VERSION 5.7 ;
  NOWIREEXTENSIONATPIN ON ;
  DIVIDERCHAR "/" ;
  BUSBITCHARS "[]" ;
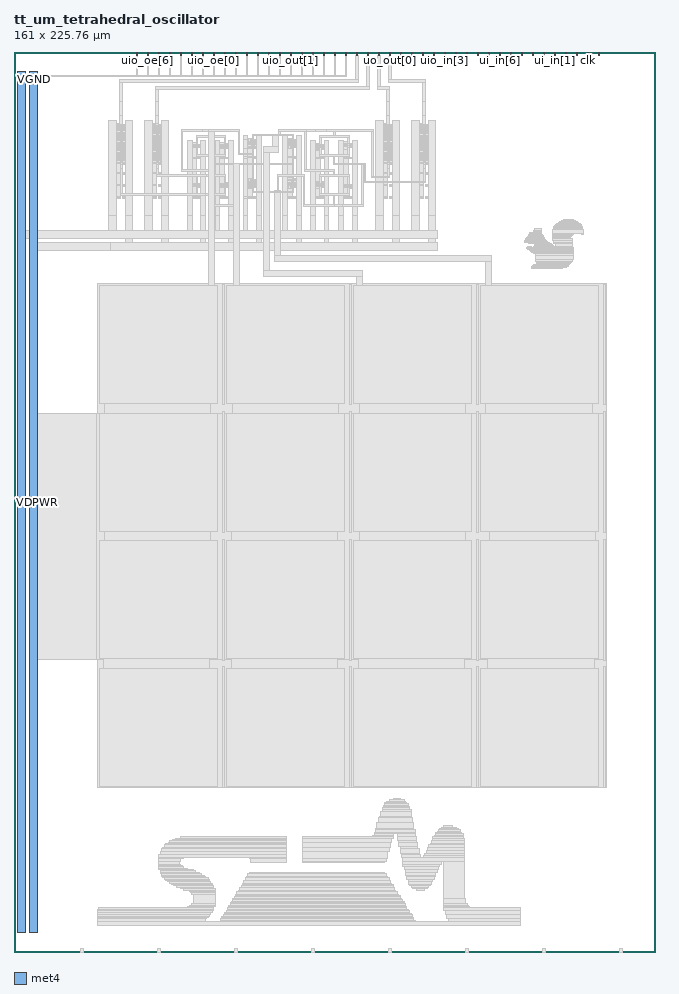
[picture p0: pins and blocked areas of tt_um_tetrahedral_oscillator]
MACRO tt_um_tetrahedral_oscillator
  CLASS BLOCK ;
  FOREIGN tt_um_tetrahedral_oscillator ;
  ORIGIN 0.000 0.000 ;
  SIZE 161.000 BY 225.760 ;
  PIN clk
    DIRECTION INPUT ;
    USE SIGNAL ;
    PORT
      LAYER met4 ;
        RECT 143.830 224.760 144.130 225.760 ;
    END
  END clk
  PIN ena
    DIRECTION INPUT ;
    USE SIGNAL ;
    PORT
      LAYER met4 ;
        RECT 146.590 224.760 146.890 225.760 ;
    END
  END ena
  PIN rst_n
    DIRECTION INPUT ;
    USE SIGNAL ;
    PORT
      LAYER met4 ;
        RECT 141.070 224.760 141.370 225.760 ;
    END
  END rst_n
  PIN ui_in[0]
    DIRECTION INPUT ;
    USE SIGNAL ;
    PORT
      LAYER met4 ;
        RECT 138.310 224.760 138.610 225.760 ;
    END
  END ui_in[0]
  PIN ui_in[1]
    DIRECTION INPUT ;
    USE SIGNAL ;
    PORT
      LAYER met4 ;
        RECT 135.550 224.760 135.850 225.760 ;
    END
  END ui_in[1]
  PIN ui_in[2]
    DIRECTION INPUT ;
    USE SIGNAL ;
    PORT
      LAYER met4 ;
        RECT 132.790 224.760 133.090 225.760 ;
    END
  END ui_in[2]
  PIN ui_in[3]
    DIRECTION INPUT ;
    USE SIGNAL ;
    PORT
      LAYER met4 ;
        RECT 130.030 224.760 130.330 225.760 ;
    END
  END ui_in[3]
  PIN ui_in[4]
    DIRECTION INPUT ;
    USE SIGNAL ;
    PORT
      LAYER met4 ;
        RECT 127.270 224.760 127.570 225.760 ;
    END
  END ui_in[4]
  PIN ui_in[5]
    DIRECTION INPUT ;
    USE SIGNAL ;
    PORT
      LAYER met4 ;
        RECT 124.510 224.760 124.810 225.760 ;
    END
  END ui_in[5]
  PIN ui_in[6]
    DIRECTION INPUT ;
    USE SIGNAL ;
    PORT
      LAYER met4 ;
        RECT 121.750 224.760 122.050 225.760 ;
    END
  END ui_in[6]
  PIN ui_in[7]
    DIRECTION INPUT ;
    USE SIGNAL ;
    PORT
      LAYER met4 ;
        RECT 118.990 224.760 119.290 225.760 ;
    END
  END ui_in[7]
  PIN uio_in[0]
    DIRECTION INPUT ;
    USE SIGNAL ;
    PORT
      LAYER met4 ;
        RECT 116.230 224.760 116.530 225.760 ;
    END
  END uio_in[0]
  PIN uio_in[1]
    DIRECTION INPUT ;
    USE SIGNAL ;
    PORT
      LAYER met4 ;
        RECT 113.470 224.760 113.770 225.760 ;
    END
  END uio_in[1]
  PIN uio_in[2]
    DIRECTION INPUT ;
    USE SIGNAL ;
    PORT
      LAYER met4 ;
        RECT 110.710 224.760 111.010 225.760 ;
    END
  END uio_in[2]
  PIN uio_in[3]
    DIRECTION INPUT ;
    USE SIGNAL ;
    PORT
      LAYER met4 ;
        RECT 107.950 224.760 108.250 225.760 ;
    END
  END uio_in[3]
  PIN uio_in[4]
    DIRECTION INPUT ;
    USE SIGNAL ;
    PORT
      LAYER met4 ;
        RECT 105.190 224.760 105.490 225.760 ;
    END
  END uio_in[4]
  PIN uio_in[5]
    DIRECTION INPUT ;
    USE SIGNAL ;
    PORT
      LAYER met4 ;
        RECT 102.430 224.760 102.730 225.760 ;
    END
  END uio_in[5]
  PIN uio_in[6]
    DIRECTION INPUT ;
    USE SIGNAL ;
    PORT
      LAYER met4 ;
        RECT 99.670 224.760 99.970 225.760 ;
    END
  END uio_in[6]
  PIN uio_in[7]
    DIRECTION INPUT ;
    USE SIGNAL ;
    PORT
      LAYER met4 ;
        RECT 96.910 224.760 97.210 225.760 ;
    END
  END uio_in[7]
  PIN uio_oe[0]
    DIRECTION OUTPUT ;
    USE SIGNAL ;
    ANTENNADIFFAREA 14.596000 ;
    PORT
      LAYER met4 ;
        RECT 49.990 224.760 50.290 225.760 ;
    END
  END uio_oe[0]
  PIN uio_oe[1]
    DIRECTION OUTPUT ;
    USE SIGNAL ;
    ANTENNADIFFAREA 14.596000 ;
    PORT
      LAYER met4 ;
        RECT 47.230 224.760 47.530 225.760 ;
    END
  END uio_oe[1]
  PIN uio_oe[2]
    DIRECTION OUTPUT ;
    USE SIGNAL ;
    ANTENNADIFFAREA 14.596000 ;
    PORT
      LAYER met4 ;
        RECT 44.470 224.760 44.770 225.760 ;
    END
  END uio_oe[2]
  PIN uio_oe[3]
    DIRECTION OUTPUT ;
    USE SIGNAL ;
    ANTENNADIFFAREA 14.596000 ;
    PORT
      LAYER met4 ;
        RECT 41.710 224.760 42.010 225.760 ;
    END
  END uio_oe[3]
  PIN uio_oe[4]
    DIRECTION OUTPUT ;
    USE SIGNAL ;
    ANTENNADIFFAREA 14.596000 ;
    PORT
      LAYER met4 ;
        RECT 38.950 224.760 39.250 225.760 ;
    END
  END uio_oe[4]
  PIN uio_oe[5]
    DIRECTION OUTPUT ;
    USE SIGNAL ;
    ANTENNADIFFAREA 14.596000 ;
    PORT
      LAYER met4 ;
        RECT 36.190 224.760 36.490 225.760 ;
    END
  END uio_oe[5]
  PIN uio_oe[6]
    DIRECTION OUTPUT ;
    USE SIGNAL ;
    ANTENNADIFFAREA 14.596000 ;
    PORT
      LAYER met4 ;
        RECT 33.430 224.760 33.730 225.760 ;
    END
  END uio_oe[6]
  PIN uio_oe[7]
    DIRECTION OUTPUT ;
    USE SIGNAL ;
    ANTENNADIFFAREA 14.596000 ;
    PORT
      LAYER met4 ;
        RECT 30.670 224.760 30.970 225.760 ;
    END
  END uio_oe[7]
  PIN uio_out[0]
    DIRECTION OUTPUT ;
    USE SIGNAL ;
    ANTENNADIFFAREA 14.596000 ;
    PORT
      LAYER met4 ;
        RECT 72.070 224.760 72.370 225.760 ;
    END
  END uio_out[0]
  PIN uio_out[1]
    DIRECTION OUTPUT ;
    USE SIGNAL ;
    ANTENNADIFFAREA 14.596000 ;
    PORT
      LAYER met4 ;
        RECT 69.310 224.760 69.610 225.760 ;
    END
  END uio_out[1]
  PIN uio_out[2]
    DIRECTION OUTPUT ;
    USE SIGNAL ;
    ANTENNADIFFAREA 14.596000 ;
    PORT
      LAYER met4 ;
        RECT 66.550 224.760 66.850 225.760 ;
    END
  END uio_out[2]
  PIN uio_out[3]
    DIRECTION OUTPUT ;
    USE SIGNAL ;
    ANTENNADIFFAREA 14.596000 ;
    PORT
      LAYER met4 ;
        RECT 63.790 224.760 64.090 225.760 ;
    END
  END uio_out[3]
  PIN uio_out[4]
    DIRECTION OUTPUT ;
    USE SIGNAL ;
    ANTENNADIFFAREA 14.596000 ;
    PORT
      LAYER met4 ;
        RECT 61.030 224.760 61.330 225.760 ;
    END
  END uio_out[4]
  PIN uio_out[5]
    DIRECTION OUTPUT ;
    USE SIGNAL ;
    ANTENNADIFFAREA 14.596000 ;
    PORT
      LAYER met4 ;
        RECT 58.270 224.760 58.570 225.760 ;
    END
  END uio_out[5]
  PIN uio_out[6]
    DIRECTION OUTPUT ;
    USE SIGNAL ;
    ANTENNADIFFAREA 14.596000 ;
    PORT
      LAYER met4 ;
        RECT 55.510 224.760 55.810 225.760 ;
    END
  END uio_out[6]
  PIN uio_out[7]
    DIRECTION OUTPUT ;
    USE SIGNAL ;
    ANTENNADIFFAREA 14.596000 ;
    PORT
      LAYER met4 ;
        RECT 52.750 224.760 53.050 225.760 ;
    END
  END uio_out[7]
  PIN uo_out[0]
    DIRECTION OUTPUT ;
    USE SIGNAL ;
    ANTENNADIFFAREA 3.564000 ;
    PORT
      LAYER met4 ;
        RECT 94.150 224.760 94.450 225.760 ;
    END
  END uo_out[0]
  PIN uo_out[1]
    DIRECTION OUTPUT ;
    USE SIGNAL ;
    ANTENNADIFFAREA 3.564000 ;
    PORT
      LAYER met4 ;
        RECT 91.390 224.760 91.690 225.760 ;
    END
  END uo_out[1]
  PIN uo_out[2]
    DIRECTION OUTPUT ;
    USE SIGNAL ;
    ANTENNADIFFAREA 3.564000 ;
    PORT
      LAYER met4 ;
        RECT 88.630 224.760 88.930 225.760 ;
    END
  END uo_out[2]
  PIN uo_out[3]
    DIRECTION OUTPUT ;
    USE SIGNAL ;
    ANTENNADIFFAREA 3.564000 ;
    PORT
      LAYER met4 ;
        RECT 85.870 224.760 86.170 225.760 ;
    END
  END uo_out[3]
  PIN uo_out[4]
    DIRECTION OUTPUT ;
    USE SIGNAL ;
    ANTENNADIFFAREA 14.596000 ;
    PORT
      LAYER met4 ;
        RECT 83.110 224.760 83.410 225.760 ;
    END
  END uo_out[4]
  PIN uo_out[5]
    DIRECTION OUTPUT ;
    USE SIGNAL ;
    ANTENNADIFFAREA 14.596000 ;
    PORT
      LAYER met4 ;
        RECT 80.350 224.760 80.650 225.760 ;
    END
  END uo_out[5]
  PIN uo_out[6]
    DIRECTION OUTPUT ;
    USE SIGNAL ;
    ANTENNADIFFAREA 14.596000 ;
    PORT
      LAYER met4 ;
        RECT 77.590 224.760 77.890 225.760 ;
    END
  END uo_out[6]
  PIN uo_out[7]
    DIRECTION OUTPUT ;
    USE SIGNAL ;
    ANTENNADIFFAREA 14.596000 ;
    PORT
      LAYER met4 ;
        RECT 74.830 224.760 75.130 225.760 ;
    END
  END uo_out[7]
  PIN VDPWR
    DIRECTION INOUT ;
    USE POWER ;
    PORT
      LAYER met4 ;
        RECT 1.000 5.000 3.000 220.760 ;
    END
  END VDPWR
  PIN VGND
    DIRECTION INOUT ;
    USE GROUND ;
    PORT
      LAYER met4 ;
        RECT 4.000 5.000 6.000 220.760 ;
    END
  END VGND
  OBS
      LAYER nwell ;
        RECT 25.205 188.930 26.810 207.915 ;
      LAYER pwell ;
        RECT 27.100 197.925 28.010 207.360 ;
        RECT 27.100 197.755 28.200 197.925 ;
        RECT 27.100 197.610 28.010 197.755 ;
        RECT 27.140 195.135 27.925 195.565 ;
        RECT 27.140 192.135 27.925 192.565 ;
        RECT 27.140 189.135 27.925 189.565 ;
      LAYER nwell ;
        RECT 34.205 188.930 35.810 207.940 ;
      LAYER pwell ;
        RECT 36.100 197.950 37.010 207.385 ;
        RECT 36.100 197.780 37.200 197.950 ;
        RECT 36.100 197.635 37.010 197.780 ;
        RECT 36.140 195.135 36.925 195.565 ;
        RECT 36.140 192.135 36.925 192.565 ;
        RECT 36.140 189.135 36.925 189.565 ;
      LAYER nwell ;
        RECT 44.205 188.930 45.810 203.015 ;
      LAYER pwell ;
        RECT 47.030 202.615 47.200 202.680 ;
        RECT 46.100 202.510 47.200 202.615 ;
        RECT 46.100 201.685 47.010 202.510 ;
        RECT 46.140 198.935 46.925 199.365 ;
        RECT 46.100 191.945 47.010 192.770 ;
        RECT 46.100 191.840 47.200 191.945 ;
        RECT 47.030 191.775 47.200 191.840 ;
        RECT 46.140 189.135 46.925 189.565 ;
      LAYER nwell ;
        RECT 51.205 188.930 52.810 202.985 ;
      LAYER pwell ;
        RECT 53.100 202.650 54.010 202.780 ;
        RECT 53.100 202.480 54.200 202.650 ;
        RECT 53.100 201.430 54.010 202.480 ;
      LAYER nwell ;
        RECT 58.205 201.430 59.815 204.110 ;
      LAYER pwell ;
        RECT 60.105 201.930 61.015 203.860 ;
      LAYER nwell ;
        RECT 68.230 203.035 69.840 204.110 ;
      LAYER pwell ;
        RECT 60.105 201.760 61.195 201.930 ;
        RECT 60.105 201.670 61.015 201.760 ;
      LAYER nwell ;
        RECT 68.205 201.430 69.840 203.035 ;
      LAYER pwell ;
        RECT 70.130 203.780 71.040 203.870 ;
        RECT 70.130 203.610 71.220 203.780 ;
        RECT 70.130 201.680 71.040 203.610 ;
      LAYER nwell ;
        RECT 82.210 202.835 83.815 203.185 ;
        RECT 75.205 202.785 76.810 202.835 ;
      LAYER pwell ;
        RECT 53.140 198.935 53.925 199.365 ;
      LAYER nwell ;
        RECT 58.205 194.090 59.810 201.430 ;
      LAYER pwell ;
        RECT 60.140 199.135 60.925 199.565 ;
      LAYER nwell ;
        RECT 68.205 194.160 69.810 201.430 ;
        RECT 75.205 201.025 76.815 202.785 ;
      LAYER pwell ;
        RECT 77.105 202.450 78.015 202.580 ;
        RECT 77.105 202.280 78.205 202.450 ;
        RECT 77.105 201.230 78.015 202.280 ;
      LAYER nwell ;
        RECT 82.205 201.425 83.815 202.835 ;
      LAYER pwell ;
        RECT 85.035 202.785 85.205 202.850 ;
        RECT 84.105 202.680 85.205 202.785 ;
        RECT 84.105 201.855 85.015 202.680 ;
        RECT 70.140 199.135 70.925 199.565 ;
        RECT 53.100 191.960 54.010 193.010 ;
        RECT 53.100 191.790 54.200 191.960 ;
        RECT 53.100 191.660 54.010 191.790 ;
      LAYER nwell ;
        RECT 58.200 191.410 59.810 194.090 ;
      LAYER pwell ;
        RECT 60.100 191.910 61.010 193.840 ;
        RECT 60.100 191.740 61.190 191.910 ;
        RECT 60.100 191.650 61.010 191.740 ;
      LAYER nwell ;
        RECT 68.200 191.480 69.810 194.160 ;
      LAYER pwell ;
        RECT 70.100 193.830 71.010 193.920 ;
        RECT 70.100 193.660 71.190 193.830 ;
        RECT 70.100 191.730 71.010 193.660 ;
      LAYER nwell ;
        RECT 75.205 193.400 76.810 201.025 ;
      LAYER pwell ;
        RECT 77.140 198.935 77.925 199.365 ;
      LAYER nwell ;
        RECT 75.200 191.640 76.810 193.400 ;
      LAYER pwell ;
        RECT 77.095 192.145 78.005 193.195 ;
        RECT 77.095 191.975 78.195 192.145 ;
        RECT 77.095 191.845 78.005 191.975 ;
        RECT 53.140 189.135 53.925 189.565 ;
      LAYER nwell ;
        RECT 58.205 188.930 59.810 191.410 ;
      LAYER pwell ;
        RECT 60.140 189.135 60.925 189.565 ;
      LAYER nwell ;
        RECT 68.205 188.930 69.810 191.480 ;
      LAYER pwell ;
        RECT 70.140 189.135 70.925 189.565 ;
      LAYER nwell ;
        RECT 75.205 188.930 76.810 191.640 ;
      LAYER pwell ;
        RECT 77.140 189.135 77.925 189.565 ;
      LAYER nwell ;
        RECT 82.205 188.930 83.810 201.425 ;
      LAYER pwell ;
        RECT 84.140 198.935 84.925 199.365 ;
        RECT 84.100 191.740 85.010 192.565 ;
        RECT 84.100 191.635 85.200 191.740 ;
        RECT 85.030 191.570 85.200 191.635 ;
        RECT 84.140 189.135 84.925 189.565 ;
      LAYER nwell ;
        RECT 92.205 188.920 93.810 207.935 ;
      LAYER pwell ;
        RECT 94.100 197.945 95.010 207.380 ;
        RECT 94.100 197.775 95.200 197.945 ;
        RECT 94.100 197.630 95.010 197.775 ;
        RECT 94.140 195.135 94.925 195.565 ;
        RECT 94.140 192.135 94.925 192.565 ;
        RECT 94.140 189.135 94.925 189.565 ;
      LAYER nwell ;
        RECT 101.205 188.930 102.810 207.940 ;
      LAYER pwell ;
        RECT 103.100 197.950 104.010 207.385 ;
        RECT 103.100 197.780 104.200 197.950 ;
        RECT 103.100 197.635 104.010 197.780 ;
        RECT 103.140 195.135 103.925 195.565 ;
        RECT 103.140 192.135 103.925 192.565 ;
        RECT 103.140 189.135 103.925 189.565 ;
      LAYER li1 ;
        RECT 25.310 207.190 25.480 207.725 ;
        RECT 25.755 207.365 27.750 207.640 ;
        RECT 26.500 207.260 27.380 207.365 ;
        RECT 25.310 207.020 26.280 207.190 ;
        RECT 25.310 206.350 25.480 207.020 ;
        RECT 26.500 206.850 26.670 207.260 ;
        RECT 25.650 206.520 26.670 206.850 ;
        RECT 25.310 206.180 26.280 206.350 ;
        RECT 25.310 205.510 25.480 206.180 ;
        RECT 26.500 206.010 26.670 206.520 ;
        RECT 25.650 205.680 26.670 206.010 ;
        RECT 25.310 205.340 26.280 205.510 ;
        RECT 25.310 204.670 25.480 205.340 ;
        RECT 26.500 205.170 26.670 205.680 ;
        RECT 25.650 204.840 26.670 205.170 ;
        RECT 25.310 204.500 26.280 204.670 ;
        RECT 25.310 203.830 25.480 204.500 ;
        RECT 26.500 204.330 26.670 204.840 ;
        RECT 25.650 204.000 26.670 204.330 ;
        RECT 25.310 203.660 26.280 203.830 ;
        RECT 25.310 202.990 25.480 203.660 ;
        RECT 26.500 203.490 26.670 204.000 ;
        RECT 25.650 203.160 26.670 203.490 ;
        RECT 25.310 202.820 26.280 202.990 ;
        RECT 25.310 202.150 25.480 202.820 ;
        RECT 26.500 202.650 26.670 203.160 ;
        RECT 25.650 202.320 26.670 202.650 ;
        RECT 25.310 201.980 26.280 202.150 ;
        RECT 25.310 201.310 25.480 201.980 ;
        RECT 26.500 201.810 26.670 202.320 ;
        RECT 25.650 201.480 26.670 201.810 ;
        RECT 25.310 201.140 26.280 201.310 ;
        RECT 25.310 200.470 25.480 201.140 ;
        RECT 26.500 200.970 26.670 201.480 ;
        RECT 25.650 200.640 26.670 200.970 ;
        RECT 26.840 200.470 27.040 207.015 ;
        RECT 27.210 206.850 27.380 207.260 ;
        RECT 28.030 207.190 28.200 207.725 ;
        RECT 27.550 207.020 28.200 207.190 ;
        RECT 27.210 206.520 27.855 206.850 ;
        RECT 27.210 206.010 27.380 206.520 ;
        RECT 28.030 206.350 28.200 207.020 ;
        RECT 27.550 206.180 28.200 206.350 ;
        RECT 27.210 205.680 27.855 206.010 ;
        RECT 27.210 205.170 27.380 205.680 ;
        RECT 28.030 205.510 28.200 206.180 ;
        RECT 27.550 205.340 28.200 205.510 ;
        RECT 27.210 204.840 27.855 205.170 ;
        RECT 27.210 204.330 27.380 204.840 ;
        RECT 28.030 204.670 28.200 205.340 ;
        RECT 27.550 204.500 28.200 204.670 ;
        RECT 27.210 204.000 27.855 204.330 ;
        RECT 27.210 203.490 27.380 204.000 ;
        RECT 28.030 203.830 28.200 204.500 ;
        RECT 27.550 203.660 28.200 203.830 ;
        RECT 27.210 203.160 27.855 203.490 ;
        RECT 27.210 202.650 27.380 203.160 ;
        RECT 28.030 202.990 28.200 203.660 ;
        RECT 27.550 202.820 28.200 202.990 ;
        RECT 27.210 202.570 27.855 202.650 ;
        RECT 27.210 202.400 27.860 202.570 ;
        RECT 27.210 202.320 27.855 202.400 ;
        RECT 27.210 201.810 27.380 202.320 ;
        RECT 28.030 202.150 28.200 202.820 ;
        RECT 27.550 201.980 28.200 202.150 ;
        RECT 27.210 201.730 27.855 201.810 ;
        RECT 27.210 201.560 27.860 201.730 ;
        RECT 27.210 201.480 27.855 201.560 ;
        RECT 27.210 200.970 27.380 201.480 ;
        RECT 28.030 201.310 28.200 201.980 ;
        RECT 27.550 201.140 28.200 201.310 ;
        RECT 27.210 200.890 27.855 200.970 ;
        RECT 27.210 200.640 27.860 200.890 ;
        RECT 28.030 200.470 28.200 201.140 ;
        RECT 25.310 200.300 26.280 200.470 ;
        RECT 25.310 199.630 25.480 200.300 ;
        RECT 26.500 200.295 27.380 200.470 ;
        RECT 27.550 200.300 28.200 200.470 ;
        RECT 26.500 200.130 26.670 200.295 ;
        RECT 25.650 199.800 26.670 200.130 ;
        RECT 27.210 200.130 27.380 200.295 ;
        RECT 25.310 199.460 26.280 199.630 ;
        RECT 25.310 198.790 25.480 199.460 ;
        RECT 26.500 199.290 26.670 199.800 ;
        RECT 25.650 198.960 26.670 199.290 ;
        RECT 25.310 198.620 26.280 198.790 ;
        RECT 25.310 197.950 25.480 198.620 ;
        RECT 26.500 198.450 26.670 198.960 ;
        RECT 25.650 198.120 26.670 198.450 ;
        RECT 25.310 197.780 26.670 197.950 ;
        RECT 25.310 197.605 25.480 197.780 ;
        RECT 26.840 197.690 27.040 200.090 ;
        RECT 27.210 199.800 27.855 200.130 ;
        RECT 27.210 199.290 27.380 199.800 ;
        RECT 28.030 199.630 28.200 200.300 ;
        RECT 27.550 199.460 28.200 199.630 ;
        RECT 27.210 198.960 27.855 199.290 ;
        RECT 27.210 198.450 27.380 198.960 ;
        RECT 28.030 198.790 28.200 199.460 ;
        RECT 27.550 198.620 28.200 198.790 ;
        RECT 27.210 198.120 27.855 198.450 ;
        RECT 28.030 197.950 28.200 198.620 ;
        RECT 27.210 197.780 28.200 197.950 ;
        RECT 28.030 197.605 28.200 197.780 ;
        RECT 34.310 207.215 34.480 207.750 ;
        RECT 34.755 207.390 36.750 207.665 ;
        RECT 35.500 207.285 36.380 207.390 ;
        RECT 34.310 207.045 35.280 207.215 ;
        RECT 34.310 206.375 34.480 207.045 ;
        RECT 35.500 206.875 35.670 207.285 ;
        RECT 34.650 206.545 35.670 206.875 ;
        RECT 34.310 206.205 35.280 206.375 ;
        RECT 34.310 205.535 34.480 206.205 ;
        RECT 35.500 206.035 35.670 206.545 ;
        RECT 34.650 205.705 35.670 206.035 ;
        RECT 34.310 205.365 35.280 205.535 ;
        RECT 34.310 204.695 34.480 205.365 ;
        RECT 35.500 205.195 35.670 205.705 ;
        RECT 34.650 204.865 35.670 205.195 ;
        RECT 34.310 204.525 35.280 204.695 ;
        RECT 34.310 203.855 34.480 204.525 ;
        RECT 35.500 204.355 35.670 204.865 ;
        RECT 34.650 204.025 35.670 204.355 ;
        RECT 34.310 203.685 35.280 203.855 ;
        RECT 34.310 203.015 34.480 203.685 ;
        RECT 35.500 203.515 35.670 204.025 ;
        RECT 34.650 203.185 35.670 203.515 ;
        RECT 34.310 202.845 35.280 203.015 ;
        RECT 34.310 202.175 34.480 202.845 ;
        RECT 35.500 202.675 35.670 203.185 ;
        RECT 34.650 202.345 35.670 202.675 ;
        RECT 34.310 202.005 35.280 202.175 ;
        RECT 34.310 201.335 34.480 202.005 ;
        RECT 35.500 201.835 35.670 202.345 ;
        RECT 34.650 201.505 35.670 201.835 ;
        RECT 34.310 201.165 35.280 201.335 ;
        RECT 34.310 200.495 34.480 201.165 ;
        RECT 35.500 200.995 35.670 201.505 ;
        RECT 34.650 200.665 35.670 200.995 ;
        RECT 35.840 200.495 36.040 207.040 ;
        RECT 36.210 206.875 36.380 207.285 ;
        RECT 37.030 207.215 37.200 207.750 ;
        RECT 36.550 207.045 37.200 207.215 ;
        RECT 36.210 206.545 36.855 206.875 ;
        RECT 36.210 206.035 36.380 206.545 ;
        RECT 37.030 206.375 37.200 207.045 ;
        RECT 36.550 206.205 37.200 206.375 ;
        RECT 36.210 205.705 36.855 206.035 ;
        RECT 36.210 205.195 36.380 205.705 ;
        RECT 37.030 205.535 37.200 206.205 ;
        RECT 36.550 205.365 37.200 205.535 ;
        RECT 36.210 204.865 36.855 205.195 ;
        RECT 36.210 204.355 36.380 204.865 ;
        RECT 37.030 204.695 37.200 205.365 ;
        RECT 36.550 204.525 37.200 204.695 ;
        RECT 36.210 204.025 36.855 204.355 ;
        RECT 36.210 203.515 36.380 204.025 ;
        RECT 37.030 203.855 37.200 204.525 ;
        RECT 92.310 207.210 92.480 207.745 ;
        RECT 92.755 207.385 94.750 207.660 ;
        RECT 93.500 207.280 94.380 207.385 ;
        RECT 92.310 207.040 93.280 207.210 ;
        RECT 92.310 206.370 92.480 207.040 ;
        RECT 93.500 206.870 93.670 207.280 ;
        RECT 92.650 206.540 93.670 206.870 ;
        RECT 92.310 206.200 93.280 206.370 ;
        RECT 92.310 205.530 92.480 206.200 ;
        RECT 93.500 206.030 93.670 206.540 ;
        RECT 92.650 205.700 93.670 206.030 ;
        RECT 92.310 205.360 93.280 205.530 ;
        RECT 92.310 204.690 92.480 205.360 ;
        RECT 93.500 205.190 93.670 205.700 ;
        RECT 92.650 204.860 93.670 205.190 ;
        RECT 92.310 204.520 93.280 204.690 ;
        RECT 36.550 203.685 37.200 203.855 ;
        RECT 36.210 203.185 36.855 203.515 ;
        RECT 36.210 202.675 36.380 203.185 ;
        RECT 37.030 203.015 37.200 203.685 ;
        RECT 36.550 202.845 37.200 203.015 ;
        RECT 36.210 202.595 36.855 202.675 ;
        RECT 36.210 202.425 36.860 202.595 ;
        RECT 36.210 202.345 36.855 202.425 ;
        RECT 36.210 201.835 36.380 202.345 ;
        RECT 37.030 202.175 37.200 202.845 ;
        RECT 58.315 203.730 58.485 203.920 ;
        RECT 58.315 203.520 58.945 203.730 ;
        RECT 59.435 203.520 60.395 203.790 ;
        RECT 61.035 203.770 61.205 203.920 ;
        RECT 60.565 203.520 61.205 203.770 ;
        RECT 58.315 202.850 58.485 203.520 ;
        RECT 59.435 203.350 59.625 203.520 ;
        RECT 60.215 203.350 60.395 203.520 ;
        RECT 58.655 203.020 59.625 203.350 ;
        RECT 36.550 202.005 37.200 202.175 ;
        RECT 36.210 201.755 36.855 201.835 ;
        RECT 36.210 201.585 36.860 201.755 ;
        RECT 36.210 201.505 36.855 201.585 ;
        RECT 36.210 200.995 36.380 201.505 ;
        RECT 37.030 201.335 37.200 202.005 ;
        RECT 44.310 202.485 44.480 202.825 ;
        RECT 47.030 202.505 47.200 202.825 ;
        RECT 44.310 202.275 45.620 202.485 ;
        RECT 44.310 201.445 44.480 202.275 ;
        RECT 45.800 202.175 46.040 202.505 ;
        RECT 46.210 202.275 47.200 202.505 ;
        RECT 44.650 202.005 45.630 202.105 ;
        RECT 46.230 202.005 46.860 202.105 ;
        RECT 44.650 201.775 46.860 202.005 ;
        RECT 47.030 201.445 47.200 202.275 ;
        RECT 51.310 202.670 51.480 202.795 ;
        RECT 51.310 202.440 52.620 202.670 ;
        RECT 51.310 201.770 51.480 202.440 ;
        RECT 52.790 202.360 53.040 202.690 ;
        RECT 54.030 202.670 54.200 202.795 ;
        RECT 53.210 202.440 54.200 202.670 ;
        RECT 51.650 202.190 52.630 202.270 ;
        RECT 53.230 202.190 53.860 202.270 ;
        RECT 51.650 201.940 53.860 202.190 ;
        RECT 54.030 201.770 54.200 202.440 ;
        RECT 51.310 201.560 52.620 201.770 ;
        RECT 53.210 201.560 54.200 201.770 ;
        RECT 58.315 202.680 59.285 202.850 ;
        RECT 58.315 202.010 58.485 202.680 ;
        RECT 59.455 202.510 59.625 203.020 ;
        RECT 58.655 202.180 59.625 202.510 ;
        RECT 58.315 201.750 59.625 202.010 ;
        RECT 58.315 201.620 58.485 201.750 ;
        RECT 59.795 201.720 60.045 203.350 ;
        RECT 60.215 203.020 60.865 203.350 ;
        RECT 60.215 202.510 60.395 203.020 ;
        RECT 61.035 202.850 61.205 203.520 ;
        RECT 60.575 202.680 61.205 202.850 ;
        RECT 60.215 202.180 60.865 202.510 ;
        RECT 61.035 202.010 61.205 202.680 ;
        RECT 60.575 201.750 61.205 202.010 ;
        RECT 61.035 201.620 61.205 201.750 ;
        RECT 68.340 203.790 68.510 203.920 ;
        RECT 68.340 203.530 69.650 203.790 ;
        RECT 68.340 202.860 68.510 203.530 ;
        RECT 68.680 203.030 69.650 203.360 ;
        RECT 68.340 202.690 69.310 202.860 ;
        RECT 68.340 202.020 68.510 202.690 ;
        RECT 69.480 202.520 69.650 203.030 ;
        RECT 68.680 202.190 69.650 202.520 ;
        RECT 69.820 202.190 70.070 203.820 ;
        RECT 71.060 203.790 71.230 203.920 ;
        RECT 70.600 203.530 71.230 203.790 ;
        RECT 70.240 203.030 70.890 203.360 ;
        RECT 70.240 202.520 70.420 203.030 ;
        RECT 71.060 202.860 71.230 203.530 ;
        RECT 92.310 203.850 92.480 204.520 ;
        RECT 93.500 204.350 93.670 204.860 ;
        RECT 92.650 204.020 93.670 204.350 ;
        RECT 92.310 203.680 93.280 203.850 ;
        RECT 92.310 203.010 92.480 203.680 ;
        RECT 93.500 203.510 93.670 204.020 ;
        RECT 92.650 203.180 93.670 203.510 ;
        RECT 70.600 202.690 71.230 202.860 ;
        RECT 70.240 202.190 70.890 202.520 ;
        RECT 69.460 202.020 69.650 202.190 ;
        RECT 70.240 202.020 70.420 202.190 ;
        RECT 71.060 202.020 71.230 202.690 ;
        RECT 82.315 202.655 82.485 202.995 ;
        RECT 85.035 202.675 85.205 202.995 ;
        RECT 68.340 201.810 68.970 202.020 ;
        RECT 68.340 201.620 68.510 201.810 ;
        RECT 69.460 201.750 70.420 202.020 ;
        RECT 70.590 201.770 71.230 202.020 ;
        RECT 71.060 201.620 71.230 201.770 ;
        RECT 75.315 202.470 75.485 202.595 ;
        RECT 75.315 202.240 76.625 202.470 ;
        RECT 51.310 201.415 51.480 201.560 ;
        RECT 54.030 201.415 54.200 201.560 ;
        RECT 75.315 201.570 75.485 202.240 ;
        RECT 76.795 202.160 77.045 202.490 ;
        RECT 78.035 202.470 78.205 202.595 ;
        RECT 77.215 202.240 78.205 202.470 ;
        RECT 75.655 201.990 76.635 202.070 ;
        RECT 77.235 201.990 77.865 202.070 ;
        RECT 75.655 201.740 77.865 201.990 ;
        RECT 78.035 201.570 78.205 202.240 ;
        RECT 82.315 202.445 83.625 202.655 ;
        RECT 82.315 201.615 82.485 202.445 ;
        RECT 83.805 202.345 84.045 202.675 ;
        RECT 84.215 202.445 85.205 202.675 ;
        RECT 82.655 202.175 83.635 202.275 ;
        RECT 84.235 202.175 84.865 202.275 ;
        RECT 82.655 201.945 84.865 202.175 ;
        RECT 85.035 201.615 85.205 202.445 ;
        RECT 92.310 202.840 93.280 203.010 ;
        RECT 92.310 202.170 92.480 202.840 ;
        RECT 93.500 202.670 93.670 203.180 ;
        RECT 92.650 202.340 93.670 202.670 ;
        RECT 92.310 202.000 93.280 202.170 ;
        RECT 36.550 201.165 37.200 201.335 ;
        RECT 75.315 201.360 76.625 201.570 ;
        RECT 77.215 201.360 78.205 201.570 ;
        RECT 75.315 201.215 75.485 201.360 ;
        RECT 78.035 201.215 78.205 201.360 ;
        RECT 92.310 201.330 92.480 202.000 ;
        RECT 93.500 201.830 93.670 202.340 ;
        RECT 92.650 201.500 93.670 201.830 ;
        RECT 36.210 200.915 36.855 200.995 ;
        RECT 36.210 200.665 36.860 200.915 ;
        RECT 37.030 200.495 37.200 201.165 ;
        RECT 34.310 200.325 35.280 200.495 ;
        RECT 34.310 199.655 34.480 200.325 ;
        RECT 35.500 200.320 36.380 200.495 ;
        RECT 36.550 200.325 37.200 200.495 ;
        RECT 35.500 200.155 35.670 200.320 ;
        RECT 34.650 199.825 35.670 200.155 ;
        RECT 36.210 200.155 36.380 200.320 ;
        RECT 34.310 199.485 35.280 199.655 ;
        RECT 34.310 198.815 34.480 199.485 ;
        RECT 35.500 199.315 35.670 199.825 ;
        RECT 34.650 198.985 35.670 199.315 ;
        RECT 34.310 198.645 35.280 198.815 ;
        RECT 34.310 197.975 34.480 198.645 ;
        RECT 35.500 198.475 35.670 198.985 ;
        RECT 34.650 198.145 35.670 198.475 ;
        RECT 34.310 197.805 35.670 197.975 ;
        RECT 34.310 197.630 34.480 197.805 ;
        RECT 35.840 197.715 36.040 200.115 ;
        RECT 36.210 199.825 36.855 200.155 ;
        RECT 36.210 199.315 36.380 199.825 ;
        RECT 37.030 199.655 37.200 200.325 ;
        RECT 36.550 199.485 37.200 199.655 ;
        RECT 92.310 201.160 93.280 201.330 ;
        RECT 92.310 200.490 92.480 201.160 ;
        RECT 93.500 200.990 93.670 201.500 ;
        RECT 92.650 200.660 93.670 200.990 ;
        RECT 93.840 200.490 94.040 207.035 ;
        RECT 94.210 206.870 94.380 207.280 ;
        RECT 95.030 207.210 95.200 207.745 ;
        RECT 94.550 207.040 95.200 207.210 ;
        RECT 94.210 206.540 94.855 206.870 ;
        RECT 94.210 206.030 94.380 206.540 ;
        RECT 95.030 206.370 95.200 207.040 ;
        RECT 94.550 206.200 95.200 206.370 ;
        RECT 94.210 205.700 94.855 206.030 ;
        RECT 94.210 205.190 94.380 205.700 ;
        RECT 95.030 205.530 95.200 206.200 ;
        RECT 94.550 205.360 95.200 205.530 ;
        RECT 94.210 204.860 94.855 205.190 ;
        RECT 94.210 204.350 94.380 204.860 ;
        RECT 95.030 204.690 95.200 205.360 ;
        RECT 94.550 204.520 95.200 204.690 ;
        RECT 94.210 204.020 94.855 204.350 ;
        RECT 94.210 203.510 94.380 204.020 ;
        RECT 95.030 203.850 95.200 204.520 ;
        RECT 94.550 203.680 95.200 203.850 ;
        RECT 94.210 203.180 94.855 203.510 ;
        RECT 94.210 202.670 94.380 203.180 ;
        RECT 95.030 203.010 95.200 203.680 ;
        RECT 94.550 202.840 95.200 203.010 ;
        RECT 94.210 202.590 94.855 202.670 ;
        RECT 94.210 202.420 94.860 202.590 ;
        RECT 94.210 202.340 94.855 202.420 ;
        RECT 94.210 201.830 94.380 202.340 ;
        RECT 95.030 202.170 95.200 202.840 ;
        RECT 94.550 202.000 95.200 202.170 ;
        RECT 94.210 201.750 94.855 201.830 ;
        RECT 94.210 201.580 94.860 201.750 ;
        RECT 94.210 201.500 94.855 201.580 ;
        RECT 94.210 200.990 94.380 201.500 ;
        RECT 95.030 201.330 95.200 202.000 ;
        RECT 94.550 201.160 95.200 201.330 ;
        RECT 94.210 200.910 94.855 200.990 ;
        RECT 94.210 200.660 94.860 200.910 ;
        RECT 95.030 200.490 95.200 201.160 ;
        RECT 92.310 200.320 93.280 200.490 ;
        RECT 92.310 199.650 92.480 200.320 ;
        RECT 93.500 200.315 94.380 200.490 ;
        RECT 94.550 200.320 95.200 200.490 ;
        RECT 93.500 200.150 93.670 200.315 ;
        RECT 92.650 199.820 93.670 200.150 ;
        RECT 94.210 200.150 94.380 200.315 ;
        RECT 36.210 198.985 36.855 199.315 ;
        RECT 36.210 198.475 36.380 198.985 ;
        RECT 37.030 198.815 37.200 199.485 ;
        RECT 58.310 199.495 58.480 199.580 ;
        RECT 61.030 199.495 61.200 199.580 ;
        RECT 44.310 199.295 44.480 199.380 ;
        RECT 47.030 199.295 47.200 199.380 ;
        RECT 44.310 199.005 45.645 199.295 ;
        RECT 46.305 199.005 47.200 199.295 ;
        RECT 44.310 198.920 44.480 199.005 ;
        RECT 47.030 198.920 47.200 199.005 ;
        RECT 51.310 199.295 51.480 199.380 ;
        RECT 54.030 199.295 54.200 199.380 ;
        RECT 51.310 199.005 52.645 199.295 ;
        RECT 53.305 199.005 54.200 199.295 ;
        RECT 58.310 199.205 59.645 199.495 ;
        RECT 60.305 199.205 61.200 199.495 ;
        RECT 58.310 199.120 58.480 199.205 ;
        RECT 61.030 199.120 61.200 199.205 ;
        RECT 68.310 199.495 68.480 199.580 ;
        RECT 71.030 199.495 71.200 199.580 ;
        RECT 68.310 199.205 69.645 199.495 ;
        RECT 70.305 199.205 71.200 199.495 ;
        RECT 92.310 199.480 93.280 199.650 ;
        RECT 68.310 199.120 68.480 199.205 ;
        RECT 71.030 199.120 71.200 199.205 ;
        RECT 75.310 199.295 75.480 199.380 ;
        RECT 78.030 199.295 78.200 199.380 ;
        RECT 51.310 198.920 51.480 199.005 ;
        RECT 54.030 198.920 54.200 199.005 ;
        RECT 75.310 199.005 76.645 199.295 ;
        RECT 77.305 199.005 78.200 199.295 ;
        RECT 75.310 198.920 75.480 199.005 ;
        RECT 78.030 198.920 78.200 199.005 ;
        RECT 82.310 199.295 82.480 199.380 ;
        RECT 85.030 199.295 85.200 199.380 ;
        RECT 82.310 199.005 83.645 199.295 ;
        RECT 84.305 199.005 85.200 199.295 ;
        RECT 82.310 198.920 82.480 199.005 ;
        RECT 85.030 198.920 85.200 199.005 ;
        RECT 36.550 198.645 37.200 198.815 ;
        RECT 36.210 198.145 36.855 198.475 ;
        RECT 37.030 197.975 37.200 198.645 ;
        RECT 36.210 197.805 37.200 197.975 ;
        RECT 37.030 197.630 37.200 197.805 ;
        RECT 92.310 198.810 92.480 199.480 ;
        RECT 93.500 199.310 93.670 199.820 ;
        RECT 92.650 198.980 93.670 199.310 ;
        RECT 92.310 198.640 93.280 198.810 ;
        RECT 92.310 197.970 92.480 198.640 ;
        RECT 93.500 198.470 93.670 198.980 ;
        RECT 92.650 198.140 93.670 198.470 ;
        RECT 92.310 197.800 93.670 197.970 ;
        RECT 92.310 197.625 92.480 197.800 ;
        RECT 93.840 197.710 94.040 200.110 ;
        RECT 94.210 199.820 94.855 200.150 ;
        RECT 94.210 199.310 94.380 199.820 ;
        RECT 95.030 199.650 95.200 200.320 ;
        RECT 94.550 199.480 95.200 199.650 ;
        RECT 94.210 198.980 94.855 199.310 ;
        RECT 94.210 198.470 94.380 198.980 ;
        RECT 95.030 198.810 95.200 199.480 ;
        RECT 94.550 198.640 95.200 198.810 ;
        RECT 94.210 198.140 94.855 198.470 ;
        RECT 95.030 197.970 95.200 198.640 ;
        RECT 94.210 197.800 95.200 197.970 ;
        RECT 95.030 197.625 95.200 197.800 ;
        RECT 101.310 207.215 101.480 207.750 ;
        RECT 101.755 207.390 103.750 207.665 ;
        RECT 102.500 207.285 103.380 207.390 ;
        RECT 101.310 207.045 102.280 207.215 ;
        RECT 101.310 206.375 101.480 207.045 ;
        RECT 102.500 206.875 102.670 207.285 ;
        RECT 101.650 206.545 102.670 206.875 ;
        RECT 101.310 206.205 102.280 206.375 ;
        RECT 101.310 205.535 101.480 206.205 ;
        RECT 102.500 206.035 102.670 206.545 ;
        RECT 101.650 205.705 102.670 206.035 ;
        RECT 101.310 205.365 102.280 205.535 ;
        RECT 101.310 204.695 101.480 205.365 ;
        RECT 102.500 205.195 102.670 205.705 ;
        RECT 101.650 204.865 102.670 205.195 ;
        RECT 101.310 204.525 102.280 204.695 ;
        RECT 101.310 203.855 101.480 204.525 ;
        RECT 102.500 204.355 102.670 204.865 ;
        RECT 101.650 204.025 102.670 204.355 ;
        RECT 101.310 203.685 102.280 203.855 ;
        RECT 101.310 203.015 101.480 203.685 ;
        RECT 102.500 203.515 102.670 204.025 ;
        RECT 101.650 203.185 102.670 203.515 ;
        RECT 101.310 202.845 102.280 203.015 ;
        RECT 101.310 202.175 101.480 202.845 ;
        RECT 102.500 202.675 102.670 203.185 ;
        RECT 101.650 202.345 102.670 202.675 ;
        RECT 101.310 202.005 102.280 202.175 ;
        RECT 101.310 201.335 101.480 202.005 ;
        RECT 102.500 201.835 102.670 202.345 ;
        RECT 101.650 201.505 102.670 201.835 ;
        RECT 101.310 201.165 102.280 201.335 ;
        RECT 101.310 200.495 101.480 201.165 ;
        RECT 102.500 200.995 102.670 201.505 ;
        RECT 101.650 200.665 102.670 200.995 ;
        RECT 102.840 200.495 103.040 207.040 ;
        RECT 103.210 206.875 103.380 207.285 ;
        RECT 104.030 207.215 104.200 207.750 ;
        RECT 103.550 207.045 104.200 207.215 ;
        RECT 103.210 206.545 103.855 206.875 ;
        RECT 103.210 206.035 103.380 206.545 ;
        RECT 104.030 206.375 104.200 207.045 ;
        RECT 103.550 206.205 104.200 206.375 ;
        RECT 103.210 205.705 103.855 206.035 ;
        RECT 103.210 205.195 103.380 205.705 ;
        RECT 104.030 205.535 104.200 206.205 ;
        RECT 103.550 205.365 104.200 205.535 ;
        RECT 103.210 204.865 103.855 205.195 ;
        RECT 103.210 204.355 103.380 204.865 ;
        RECT 104.030 204.695 104.200 205.365 ;
        RECT 103.550 204.525 104.200 204.695 ;
        RECT 103.210 204.025 103.855 204.355 ;
        RECT 103.210 203.515 103.380 204.025 ;
        RECT 104.030 203.855 104.200 204.525 ;
        RECT 103.550 203.685 104.200 203.855 ;
        RECT 103.210 203.185 103.855 203.515 ;
        RECT 103.210 202.675 103.380 203.185 ;
        RECT 104.030 203.015 104.200 203.685 ;
        RECT 103.550 202.845 104.200 203.015 ;
        RECT 103.210 202.595 103.855 202.675 ;
        RECT 103.210 202.425 103.860 202.595 ;
        RECT 103.210 202.345 103.855 202.425 ;
        RECT 103.210 201.835 103.380 202.345 ;
        RECT 104.030 202.175 104.200 202.845 ;
        RECT 103.550 202.005 104.200 202.175 ;
        RECT 103.210 201.755 103.855 201.835 ;
        RECT 103.210 201.585 103.860 201.755 ;
        RECT 103.210 201.505 103.855 201.585 ;
        RECT 103.210 200.995 103.380 201.505 ;
        RECT 104.030 201.335 104.200 202.005 ;
        RECT 103.550 201.165 104.200 201.335 ;
        RECT 103.210 200.915 103.855 200.995 ;
        RECT 103.210 200.665 103.860 200.915 ;
        RECT 104.030 200.495 104.200 201.165 ;
        RECT 101.310 200.325 102.280 200.495 ;
        RECT 101.310 199.655 101.480 200.325 ;
        RECT 102.500 200.320 103.380 200.495 ;
        RECT 103.550 200.325 104.200 200.495 ;
        RECT 102.500 200.155 102.670 200.320 ;
        RECT 101.650 199.825 102.670 200.155 ;
        RECT 103.210 200.155 103.380 200.320 ;
        RECT 101.310 199.485 102.280 199.655 ;
        RECT 101.310 198.815 101.480 199.485 ;
        RECT 102.500 199.315 102.670 199.825 ;
        RECT 101.650 198.985 102.670 199.315 ;
        RECT 101.310 198.645 102.280 198.815 ;
        RECT 101.310 197.975 101.480 198.645 ;
        RECT 102.500 198.475 102.670 198.985 ;
        RECT 101.650 198.145 102.670 198.475 ;
        RECT 101.310 197.805 102.670 197.975 ;
        RECT 101.310 197.630 101.480 197.805 ;
        RECT 102.840 197.715 103.040 200.115 ;
        RECT 103.210 199.825 103.855 200.155 ;
        RECT 103.210 199.315 103.380 199.825 ;
        RECT 104.030 199.655 104.200 200.325 ;
        RECT 103.550 199.485 104.200 199.655 ;
        RECT 103.210 198.985 103.855 199.315 ;
        RECT 103.210 198.475 103.380 198.985 ;
        RECT 104.030 198.815 104.200 199.485 ;
        RECT 103.550 198.645 104.200 198.815 ;
        RECT 103.210 198.145 103.855 198.475 ;
        RECT 104.030 197.975 104.200 198.645 ;
        RECT 103.210 197.805 104.200 197.975 ;
        RECT 104.030 197.630 104.200 197.805 ;
        RECT 25.310 195.495 25.480 195.580 ;
        RECT 28.030 195.495 28.200 195.580 ;
        RECT 25.310 195.205 26.645 195.495 ;
        RECT 27.305 195.205 28.200 195.495 ;
        RECT 25.310 195.120 25.480 195.205 ;
        RECT 28.030 195.120 28.200 195.205 ;
        RECT 34.310 195.495 34.480 195.580 ;
        RECT 37.030 195.495 37.200 195.580 ;
        RECT 34.310 195.205 35.645 195.495 ;
        RECT 36.305 195.205 37.200 195.495 ;
        RECT 34.310 195.120 34.480 195.205 ;
        RECT 37.030 195.120 37.200 195.205 ;
        RECT 92.310 195.495 92.480 195.580 ;
        RECT 95.030 195.495 95.200 195.580 ;
        RECT 92.310 195.205 93.645 195.495 ;
        RECT 94.305 195.205 95.200 195.495 ;
        RECT 92.310 195.120 92.480 195.205 ;
        RECT 95.030 195.120 95.200 195.205 ;
        RECT 101.310 195.495 101.480 195.580 ;
        RECT 104.030 195.495 104.200 195.580 ;
        RECT 101.310 195.205 102.645 195.495 ;
        RECT 103.305 195.205 104.200 195.495 ;
        RECT 101.310 195.120 101.480 195.205 ;
        RECT 104.030 195.120 104.200 195.205 ;
        RECT 58.310 193.710 58.480 193.900 ;
        RECT 58.310 193.500 58.940 193.710 ;
        RECT 59.430 193.500 60.390 193.770 ;
        RECT 61.030 193.750 61.200 193.900 ;
        RECT 60.560 193.500 61.200 193.750 ;
        RECT 25.310 192.495 25.480 192.580 ;
        RECT 28.030 192.495 28.200 192.580 ;
        RECT 25.310 192.205 26.645 192.495 ;
        RECT 27.305 192.205 28.200 192.495 ;
        RECT 25.310 192.120 25.480 192.205 ;
        RECT 28.030 192.120 28.200 192.205 ;
        RECT 34.310 192.495 34.480 192.580 ;
        RECT 37.030 192.495 37.200 192.580 ;
        RECT 34.310 192.205 35.645 192.495 ;
        RECT 36.305 192.205 37.200 192.495 ;
        RECT 34.310 192.120 34.480 192.205 ;
        RECT 37.030 192.120 37.200 192.205 ;
        RECT 44.310 192.180 44.480 193.010 ;
        RECT 44.650 192.450 46.860 192.680 ;
        RECT 44.650 192.350 45.630 192.450 ;
        RECT 46.230 192.350 46.860 192.450 ;
        RECT 44.310 191.970 45.620 192.180 ;
        RECT 44.310 191.630 44.480 191.970 ;
        RECT 45.800 191.950 46.040 192.280 ;
        RECT 47.030 192.180 47.200 193.010 ;
        RECT 46.210 191.950 47.200 192.180 ;
        RECT 47.030 191.630 47.200 191.950 ;
        RECT 51.310 192.880 51.480 193.025 ;
        RECT 54.030 192.880 54.200 193.025 ;
        RECT 51.310 192.670 52.620 192.880 ;
        RECT 53.210 192.670 54.200 192.880 ;
        RECT 51.310 192.000 51.480 192.670 ;
        RECT 51.650 192.250 53.860 192.500 ;
        RECT 51.650 192.170 52.630 192.250 ;
        RECT 53.230 192.170 53.860 192.250 ;
        RECT 51.310 191.770 52.620 192.000 ;
        RECT 51.310 191.645 51.480 191.770 ;
        RECT 52.790 191.750 53.040 192.080 ;
        RECT 54.030 192.000 54.200 192.670 ;
        RECT 53.210 191.770 54.200 192.000 ;
        RECT 54.030 191.645 54.200 191.770 ;
        RECT 58.310 192.830 58.480 193.500 ;
        RECT 59.430 193.330 59.620 193.500 ;
        RECT 60.210 193.330 60.390 193.500 ;
        RECT 58.650 193.000 59.620 193.330 ;
        RECT 58.310 192.660 59.280 192.830 ;
        RECT 58.310 191.990 58.480 192.660 ;
        RECT 59.450 192.490 59.620 193.000 ;
        RECT 58.650 192.160 59.620 192.490 ;
        RECT 58.310 191.730 59.620 191.990 ;
        RECT 58.310 191.600 58.480 191.730 ;
        RECT 59.790 191.700 60.040 193.330 ;
        RECT 60.210 193.000 60.860 193.330 ;
        RECT 60.210 192.490 60.390 193.000 ;
        RECT 61.030 192.830 61.200 193.500 ;
        RECT 60.570 192.660 61.200 192.830 ;
        RECT 60.210 192.160 60.860 192.490 ;
        RECT 61.030 191.990 61.200 192.660 ;
        RECT 60.570 191.730 61.200 191.990 ;
        RECT 61.030 191.600 61.200 191.730 ;
        RECT 68.310 193.840 68.480 193.970 ;
        RECT 68.310 193.580 69.620 193.840 ;
        RECT 68.310 192.910 68.480 193.580 ;
        RECT 68.650 193.080 69.620 193.410 ;
        RECT 68.310 192.740 69.280 192.910 ;
        RECT 68.310 192.070 68.480 192.740 ;
        RECT 69.450 192.570 69.620 193.080 ;
        RECT 68.650 192.240 69.620 192.570 ;
        RECT 69.790 192.240 70.040 193.870 ;
        RECT 71.030 193.840 71.200 193.970 ;
        RECT 70.570 193.580 71.200 193.840 ;
        RECT 70.210 193.080 70.860 193.410 ;
        RECT 70.210 192.570 70.390 193.080 ;
        RECT 71.030 192.910 71.200 193.580 ;
        RECT 70.570 192.740 71.200 192.910 ;
        RECT 70.210 192.240 70.860 192.570 ;
        RECT 69.430 192.070 69.620 192.240 ;
        RECT 70.210 192.070 70.390 192.240 ;
        RECT 71.030 192.070 71.200 192.740 ;
        RECT 68.310 191.860 68.940 192.070 ;
        RECT 68.310 191.670 68.480 191.860 ;
        RECT 69.430 191.800 70.390 192.070 ;
        RECT 70.560 191.820 71.200 192.070 ;
        RECT 75.305 193.065 75.475 193.210 ;
        RECT 78.025 193.065 78.195 193.210 ;
        RECT 75.305 192.855 76.615 193.065 ;
        RECT 77.205 192.855 78.195 193.065 ;
        RECT 75.305 192.185 75.475 192.855 ;
        RECT 75.645 192.435 77.855 192.685 ;
        RECT 75.645 192.355 76.625 192.435 ;
        RECT 77.225 192.355 77.855 192.435 ;
        RECT 75.305 191.955 76.615 192.185 ;
        RECT 75.305 191.830 75.475 191.955 ;
        RECT 76.785 191.935 77.035 192.265 ;
        RECT 78.025 192.185 78.195 192.855 ;
        RECT 77.205 191.955 78.195 192.185 ;
        RECT 78.025 191.830 78.195 191.955 ;
        RECT 82.310 191.975 82.480 192.805 ;
        RECT 82.650 192.245 84.860 192.475 ;
        RECT 82.650 192.145 83.630 192.245 ;
        RECT 84.230 192.145 84.860 192.245 ;
        RECT 71.030 191.670 71.200 191.820 ;
        RECT 82.310 191.765 83.620 191.975 ;
        RECT 82.310 191.425 82.480 191.765 ;
        RECT 83.800 191.745 84.040 192.075 ;
        RECT 85.030 191.975 85.200 192.805 ;
        RECT 92.310 192.495 92.480 192.580 ;
        RECT 95.030 192.495 95.200 192.580 ;
        RECT 92.310 192.205 93.645 192.495 ;
        RECT 94.305 192.205 95.200 192.495 ;
        RECT 92.310 192.120 92.480 192.205 ;
        RECT 95.030 192.120 95.200 192.205 ;
        RECT 101.310 192.495 101.480 192.580 ;
        RECT 104.030 192.495 104.200 192.580 ;
        RECT 101.310 192.205 102.645 192.495 ;
        RECT 103.305 192.205 104.200 192.495 ;
        RECT 101.310 192.120 101.480 192.205 ;
        RECT 104.030 192.120 104.200 192.205 ;
        RECT 84.210 191.745 85.200 191.975 ;
        RECT 85.030 191.425 85.200 191.745 ;
        RECT 25.310 189.495 25.480 189.580 ;
        RECT 28.030 189.495 28.200 189.580 ;
        RECT 25.310 189.205 26.645 189.495 ;
        RECT 27.305 189.205 28.200 189.495 ;
        RECT 25.310 189.120 25.480 189.205 ;
        RECT 28.030 189.120 28.200 189.205 ;
        RECT 34.310 189.495 34.480 189.580 ;
        RECT 37.030 189.495 37.200 189.580 ;
        RECT 34.310 189.205 35.645 189.495 ;
        RECT 36.305 189.205 37.200 189.495 ;
        RECT 34.310 189.120 34.480 189.205 ;
        RECT 37.030 189.120 37.200 189.205 ;
        RECT 44.310 189.495 44.480 189.580 ;
        RECT 47.030 189.495 47.200 189.580 ;
        RECT 44.310 189.205 45.645 189.495 ;
        RECT 46.305 189.205 47.200 189.495 ;
        RECT 44.310 189.120 44.480 189.205 ;
        RECT 47.030 189.120 47.200 189.205 ;
        RECT 51.310 189.495 51.480 189.580 ;
        RECT 54.030 189.495 54.200 189.580 ;
        RECT 51.310 189.205 52.645 189.495 ;
        RECT 53.305 189.205 54.200 189.495 ;
        RECT 51.310 189.120 51.480 189.205 ;
        RECT 54.030 189.120 54.200 189.205 ;
        RECT 58.310 189.495 58.480 189.580 ;
        RECT 61.030 189.495 61.200 189.580 ;
        RECT 58.310 189.205 59.645 189.495 ;
        RECT 60.305 189.205 61.200 189.495 ;
        RECT 58.310 189.120 58.480 189.205 ;
        RECT 61.030 189.120 61.200 189.205 ;
        RECT 68.310 189.495 68.480 189.580 ;
        RECT 71.030 189.495 71.200 189.580 ;
        RECT 68.310 189.205 69.645 189.495 ;
        RECT 70.305 189.205 71.200 189.495 ;
        RECT 68.310 189.120 68.480 189.205 ;
        RECT 71.030 189.120 71.200 189.205 ;
        RECT 75.310 189.495 75.480 189.580 ;
        RECT 78.030 189.495 78.200 189.580 ;
        RECT 75.310 189.205 76.645 189.495 ;
        RECT 77.305 189.205 78.200 189.495 ;
        RECT 75.310 189.120 75.480 189.205 ;
        RECT 78.030 189.120 78.200 189.205 ;
        RECT 82.310 189.495 82.480 189.580 ;
        RECT 85.030 189.495 85.200 189.580 ;
        RECT 82.310 189.205 83.645 189.495 ;
        RECT 84.305 189.205 85.200 189.495 ;
        RECT 82.310 189.120 82.480 189.205 ;
        RECT 85.030 189.120 85.200 189.205 ;
        RECT 92.310 189.495 92.480 189.580 ;
        RECT 95.030 189.495 95.200 189.580 ;
        RECT 92.310 189.205 93.645 189.495 ;
        RECT 94.305 189.205 95.200 189.495 ;
        RECT 92.310 189.120 92.480 189.205 ;
        RECT 95.030 189.120 95.200 189.205 ;
        RECT 101.310 189.495 101.480 189.580 ;
        RECT 104.030 189.495 104.200 189.580 ;
        RECT 101.310 189.205 102.645 189.495 ;
        RECT 103.305 189.205 104.200 189.495 ;
        RECT 101.310 189.120 101.480 189.205 ;
        RECT 104.030 189.120 104.200 189.205 ;
      LAYER met1 ;
        RECT 23.740 181.390 25.635 208.545 ;
        RECT 26.365 207.385 27.245 208.395 ;
        RECT 26.470 207.375 26.700 207.385 ;
        RECT 26.870 207.375 27.100 207.385 ;
        RECT 26.765 196.490 27.165 198.070 ;
        RECT 27.875 181.390 29.770 208.545 ;
        RECT 32.740 181.390 34.635 208.545 ;
        RECT 35.375 207.430 36.255 208.440 ;
        RECT 35.480 207.420 35.710 207.430 ;
        RECT 35.880 207.420 36.110 207.430 ;
        RECT 35.765 196.490 36.165 198.070 ;
        RECT 36.875 181.390 38.770 208.545 ;
        RECT 57.445 203.920 58.630 204.850 ;
        RECT 43.470 181.390 44.655 203.660 ;
        RECT 45.755 202.205 46.155 203.430 ;
        RECT 45.755 200.830 46.155 202.030 ;
        RECT 45.755 192.430 46.155 193.630 ;
        RECT 45.755 191.030 46.155 192.230 ;
        RECT 46.855 181.390 48.055 203.660 ;
        RECT 50.505 181.390 51.655 203.660 ;
        RECT 52.755 202.355 53.155 203.605 ;
        RECT 52.755 200.930 53.155 202.205 ;
        RECT 52.755 192.230 53.155 193.430 ;
        RECT 52.755 190.830 53.155 192.030 ;
        RECT 53.855 181.390 55.040 203.660 ;
        RECT 57.445 201.620 58.635 203.920 ;
        RECT 59.755 203.530 60.155 204.830 ;
        RECT 59.830 203.520 60.060 203.530 ;
        RECT 57.445 199.580 58.630 201.620 ;
        RECT 59.755 200.730 60.155 202.030 ;
        RECT 57.445 199.120 58.635 199.580 ;
        RECT 57.445 189.580 58.630 199.120 ;
        RECT 59.755 193.530 60.155 194.830 ;
        RECT 59.855 193.520 60.085 193.530 ;
        RECT 59.805 192.030 60.035 192.035 ;
        RECT 59.755 190.730 60.155 192.030 ;
        RECT 57.445 189.120 58.635 189.580 ;
        RECT 57.445 181.390 58.630 189.120 ;
        RECT 60.870 181.390 62.055 204.850 ;
        RECT 67.475 181.390 68.660 204.850 ;
        RECT 69.755 203.530 70.155 204.830 ;
        RECT 69.855 202.030 70.085 202.035 ;
        RECT 69.755 200.730 70.155 202.030 ;
        RECT 69.755 193.530 70.155 194.830 ;
        RECT 69.855 192.030 70.085 192.035 ;
        RECT 69.755 190.730 70.155 192.030 ;
        RECT 70.870 181.390 72.055 204.850 ;
        RECT 74.470 181.390 75.655 203.660 ;
        RECT 76.755 202.205 77.155 203.430 ;
        RECT 76.755 200.830 77.155 202.030 ;
        RECT 76.755 192.430 77.155 193.630 ;
        RECT 76.755 191.030 77.155 192.230 ;
        RECT 77.830 181.390 79.015 203.660 ;
        RECT 81.470 181.390 82.655 203.660 ;
        RECT 83.755 202.355 84.155 203.605 ;
        RECT 83.755 200.930 84.155 202.205 ;
        RECT 83.755 192.230 84.155 193.430 ;
        RECT 83.800 192.220 84.035 192.230 ;
        RECT 83.800 192.030 84.035 192.040 ;
        RECT 83.755 190.830 84.155 192.030 ;
        RECT 84.875 181.390 86.060 203.660 ;
        RECT 90.740 181.390 92.635 208.545 ;
        RECT 93.390 207.400 94.270 208.410 ;
        RECT 93.495 207.390 93.725 207.400 ;
        RECT 93.895 207.390 94.125 207.400 ;
        RECT 93.765 196.490 94.165 198.070 ;
        RECT 94.875 181.390 96.770 208.545 ;
        RECT 99.740 181.390 101.635 208.545 ;
        RECT 102.360 207.420 103.240 208.430 ;
        RECT 102.465 207.410 102.695 207.420 ;
        RECT 102.865 207.410 103.095 207.420 ;
        RECT 102.765 196.490 103.165 198.070 ;
        RECT 103.875 181.390 105.770 208.545 ;
      LAYER met2 ;
        RECT 26.365 207.655 27.245 210.905 ;
        RECT 35.375 207.700 36.255 210.950 ;
        RECT 93.390 207.670 94.270 210.920 ;
        RECT 102.360 207.690 103.240 210.940 ;
        RECT 41.905 205.880 49.530 206.280 ;
        RECT 26.765 193.905 27.165 197.435 ;
        RECT 35.765 194.530 36.165 197.435 ;
        RECT 41.905 196.255 42.305 205.880 ;
        RECT 49.130 204.730 49.530 205.880 ;
        RECT 72.905 205.880 80.530 206.280 ;
        RECT 59.755 204.730 70.155 205.130 ;
        RECT 45.755 204.330 53.155 204.730 ;
        RECT 45.755 202.530 46.155 204.330 ;
        RECT 52.755 202.705 53.155 204.330 ;
        RECT 59.755 203.830 60.155 204.730 ;
        RECT 69.755 203.830 70.155 204.730 ;
        RECT 45.755 200.030 46.155 201.705 ;
        RECT 52.755 200.030 53.155 201.830 ;
        RECT 59.755 200.355 60.155 201.730 ;
        RECT 45.755 199.630 53.155 200.030 ;
        RECT 57.955 199.955 60.155 200.355 ;
        RECT 49.105 197.855 49.505 199.630 ;
        RECT 49.105 197.455 56.555 197.855 ;
        RECT 41.905 195.855 49.505 196.255 ;
        RECT 49.105 194.930 49.505 195.855 ;
        RECT 45.755 194.530 53.155 194.930 ;
        RECT 45.755 192.730 46.155 194.530 ;
        RECT 52.755 192.530 53.155 194.530 ;
        RECT 45.755 190.230 46.155 192.030 ;
        RECT 52.755 190.230 53.155 191.780 ;
        RECT 45.755 189.830 53.155 190.230 ;
        RECT 49.105 187.405 49.505 189.830 ;
        RECT 56.155 187.405 56.555 197.455 ;
        RECT 59.755 193.830 60.155 199.955 ;
        RECT 69.755 197.855 70.155 201.730 ;
        RECT 68.105 197.455 70.155 197.855 ;
        RECT 69.755 193.830 70.155 197.455 ;
        RECT 72.905 196.255 73.305 205.880 ;
        RECT 80.130 204.730 80.530 205.880 ;
        RECT 76.755 204.330 84.155 204.730 ;
        RECT 76.755 202.530 77.155 204.330 ;
        RECT 83.755 202.705 84.155 204.330 ;
        RECT 76.755 200.030 77.155 201.705 ;
        RECT 83.755 200.030 84.155 201.830 ;
        RECT 76.755 199.630 84.155 200.030 ;
        RECT 80.105 197.855 80.505 199.630 ;
        RECT 80.105 197.455 87.555 197.855 ;
        RECT 72.905 195.855 80.505 196.255 ;
        RECT 80.105 194.930 80.505 195.855 ;
        RECT 76.755 194.530 84.155 194.930 ;
        RECT 76.755 192.730 77.155 194.530 ;
        RECT 83.755 192.530 84.155 194.530 ;
        RECT 59.755 190.830 60.155 191.730 ;
        RECT 69.755 190.830 70.155 191.730 ;
        RECT 59.755 190.430 70.155 190.830 ;
        RECT 76.755 190.230 77.155 192.030 ;
        RECT 83.755 190.230 84.155 191.780 ;
        RECT 76.755 189.830 84.155 190.230 ;
        RECT 49.105 187.005 56.555 187.405 ;
        RECT 80.105 187.405 80.505 189.830 ;
        RECT 87.155 187.405 87.555 197.455 ;
        RECT 93.765 194.205 94.165 197.435 ;
        RECT 102.765 194.180 103.165 197.435 ;
        RECT 80.105 187.005 87.555 187.405 ;
        RECT 23.740 178.930 25.635 184.740 ;
        RECT 27.875 177.930 29.770 184.740 ;
        RECT 32.740 178.930 34.635 184.740 ;
        RECT 36.875 177.930 38.770 184.740 ;
        RECT 43.470 178.930 44.655 184.740 ;
        RECT 46.855 177.930 48.055 184.740 ;
        RECT 50.505 178.930 51.655 184.740 ;
        RECT 53.855 177.930 55.040 184.740 ;
        RECT 57.445 178.930 58.630 184.740 ;
        RECT 60.870 177.930 62.055 184.740 ;
        RECT 67.475 178.930 68.660 184.740 ;
        RECT 70.870 177.930 72.055 184.740 ;
        RECT 74.470 178.930 75.655 184.740 ;
        RECT 77.830 177.930 79.015 184.740 ;
        RECT 81.470 178.930 82.655 184.740 ;
        RECT 84.875 177.930 86.060 184.740 ;
        RECT 90.740 178.930 92.635 184.740 ;
        RECT 94.875 177.930 96.770 184.740 ;
        RECT 99.740 178.930 101.635 184.740 ;
        RECT 103.875 177.930 105.770 184.740 ;
        RECT 23.355 175.930 106.355 177.930 ;
      LAYER met3 ;
        RECT 1.000 180.930 3.000 220.760 ;
        RECT 26.365 209.885 27.245 214.280 ;
        RECT 35.375 209.930 36.255 214.325 ;
        RECT 93.390 209.900 94.270 214.295 ;
        RECT 102.360 209.920 103.240 214.315 ;
        RECT 47.180 205.880 51.730 206.280 ;
        RECT 71.280 205.880 75.705 206.280 ;
        RECT 78.305 205.880 90.070 206.280 ;
        RECT 62.030 204.730 66.755 205.130 ;
        RECT 56.255 199.955 60.155 200.355 ;
        RECT 51.555 197.455 70.155 197.855 ;
        RECT 85.005 197.455 88.230 197.855 ;
        RECT 55.155 196.980 56.655 197.455 ;
        RECT 26.765 190.230 27.165 196.470 ;
        RECT 35.765 194.920 36.165 196.470 ;
        RECT 35.765 194.520 48.230 194.920 ;
        RECT 87.830 193.320 88.230 197.455 ;
        RECT 89.670 194.595 90.070 205.880 ;
        RECT 93.765 194.595 94.165 196.470 ;
        RECT 89.670 194.195 94.165 194.595 ;
        RECT 102.765 193.320 103.165 196.470 ;
        RECT 87.830 192.920 103.165 193.320 ;
        RECT 61.955 190.430 66.450 190.830 ;
        RECT 26.765 189.830 48.055 190.230 ;
        RECT 78.180 187.005 82.480 187.405 ;
        RECT 137.935 183.485 140.435 183.690 ;
        RECT 137.310 183.275 140.855 183.485 ;
        RECT 136.895 183.065 141.270 183.275 ;
        RECT 136.480 182.860 141.685 183.065 ;
        RECT 136.270 182.650 141.895 182.860 ;
        RECT 136.060 182.440 142.105 182.650 ;
        RECT 135.855 182.235 142.310 182.440 ;
        RECT 135.645 182.025 142.310 182.235 ;
        RECT 135.435 181.815 142.520 182.025 ;
        RECT 135.435 181.610 142.730 181.815 ;
        RECT 130.855 181.400 131.270 181.610 ;
        RECT 131.895 181.400 132.310 181.610 ;
        RECT 130.645 180.985 132.310 181.400 ;
        RECT 135.230 181.190 142.730 181.610 ;
        RECT 1.000 178.930 106.355 180.930 ;
        RECT 130.435 180.775 132.310 180.985 ;
        RECT 130.230 180.565 132.310 180.775 ;
        RECT 129.810 180.360 132.310 180.565 ;
        RECT 129.395 180.150 132.310 180.360 ;
        RECT 129.185 179.940 132.310 180.150 ;
        RECT 135.020 180.150 142.935 181.190 ;
        RECT 135.020 179.940 140.435 180.150 ;
        RECT 142.310 179.940 142.935 180.150 ;
        RECT 128.980 179.735 132.520 179.940 ;
        RECT 135.020 179.735 140.020 179.940 ;
        RECT 128.980 179.525 132.730 179.735 ;
        RECT 128.770 179.315 132.730 179.525 ;
        RECT 135.020 179.525 139.810 179.735 ;
        RECT 135.020 179.315 139.605 179.525 ;
        RECT 128.560 179.110 132.935 179.315 ;
        RECT 1.000 5.000 3.000 178.930 ;
        RECT 128.560 178.900 133.145 179.110 ;
        RECT 128.355 178.690 133.145 178.900 ;
        RECT 135.020 178.900 139.395 179.315 ;
        RECT 128.355 178.485 133.355 178.690 ;
        RECT 135.020 178.485 140.020 178.900 ;
        RECT 128.145 178.275 133.560 178.485 ;
        RECT 128.145 178.065 133.770 178.275 ;
        RECT 135.230 178.065 140.020 178.485 ;
        RECT 17.755 175.930 106.355 177.930 ;
        RECT 128.560 177.860 133.980 178.065 ;
        RECT 128.980 177.650 134.395 177.860 ;
        RECT 135.435 177.650 140.020 178.065 ;
        RECT 130.645 177.440 134.810 177.650 ;
        RECT 135.645 177.635 140.020 177.650 ;
        RECT 130.645 177.235 135.020 177.440 ;
        RECT 130.645 177.025 135.435 177.235 ;
        RECT 135.835 177.025 140.020 177.635 ;
        RECT 128.770 176.815 129.810 177.025 ;
        RECT 130.435 176.815 140.020 177.025 ;
        RECT 128.560 176.610 140.020 176.815 ;
        RECT 128.560 176.400 140.230 176.610 ;
        RECT 128.770 176.190 140.230 176.400 ;
        RECT 129.395 175.985 140.230 176.190 ;
        RECT 129.605 175.775 140.230 175.985 ;
        RECT 129.810 175.565 140.230 175.775 ;
        RECT 130.020 175.360 140.230 175.565 ;
        RECT 130.435 175.150 140.435 175.360 ;
        RECT 130.855 174.735 140.435 175.150 ;
        RECT 130.855 173.690 140.230 174.735 ;
        RECT 130.855 173.275 140.020 173.690 ;
        RECT 131.060 172.860 139.810 173.275 ;
        RECT 131.185 172.650 139.605 172.860 ;
        RECT 131.185 172.440 139.395 172.650 ;
        RECT 130.435 172.235 139.185 172.440 ;
        RECT 130.020 172.025 138.980 172.235 ;
        RECT 129.810 171.815 138.560 172.025 ;
        RECT 129.810 171.610 138.145 171.815 ;
        RECT 129.810 171.400 137.520 171.610 ;
        RECT 20.930 135.015 148.500 167.650 ;
        RECT 4.000 73.465 148.500 135.015 ;
        RECT 20.930 41.180 148.500 73.465 ;
      LAYER met4 ;
        RECT 85.555 224.760 85.870 224.775 ;
        RECT 86.170 224.760 86.435 224.775 ;
        RECT 91.135 224.760 91.390 224.765 ;
        RECT 91.690 224.760 92.015 224.765 ;
        RECT 30.670 219.960 30.970 224.760 ;
        RECT 33.430 219.960 33.730 224.760 ;
        RECT 36.190 219.960 36.490 224.760 ;
        RECT 38.950 219.960 39.250 224.760 ;
        RECT 41.710 219.960 42.010 224.760 ;
        RECT 44.470 219.960 44.770 224.760 ;
        RECT 47.230 219.960 47.530 224.760 ;
        RECT 49.990 219.960 50.290 224.760 ;
        RECT 52.750 219.960 53.050 224.760 ;
        RECT 55.510 219.960 55.810 224.760 ;
        RECT 58.270 219.960 58.570 224.760 ;
        RECT 61.030 219.960 61.330 224.760 ;
        RECT 63.790 219.960 64.090 224.760 ;
        RECT 66.550 219.960 66.850 224.760 ;
        RECT 69.310 219.960 69.610 224.760 ;
        RECT 72.070 219.960 72.370 224.760 ;
        RECT 74.830 219.960 75.130 224.760 ;
        RECT 77.590 219.960 77.890 224.760 ;
        RECT 80.350 219.960 80.650 224.760 ;
        RECT 83.110 219.960 83.410 224.760 ;
        RECT 6.000 219.660 83.410 219.960 ;
        RECT 47.230 219.630 47.530 219.660 ;
        RECT 69.310 219.630 69.610 219.660 ;
        RECT 85.555 218.885 86.435 224.760 ;
        RECT 88.630 224.740 88.930 224.760 ;
        RECT 26.365 218.005 86.435 218.885 ;
        RECT 26.365 213.270 27.245 218.005 ;
        RECT 88.340 217.125 89.220 224.740 ;
        RECT 35.375 216.245 89.220 217.125 ;
        RECT 91.135 217.120 92.015 224.760 ;
        RECT 94.150 224.735 94.450 224.760 ;
        RECT 93.855 218.890 94.735 224.735 ;
        RECT 93.855 218.010 103.240 218.890 ;
        RECT 35.375 213.315 36.255 216.245 ;
        RECT 91.135 216.240 94.270 217.120 ;
        RECT 93.390 213.285 94.270 216.240 ;
        RECT 102.360 213.305 103.240 218.010 ;
        RECT 48.855 206.280 50.355 206.430 ;
        RECT 48.855 205.880 56.655 206.280 ;
        RECT 15.855 177.860 24.155 177.930 ;
        RECT 6.000 175.930 24.155 177.860 ;
        RECT 48.855 167.185 50.355 205.880 ;
        RECT 56.255 200.355 56.655 205.880 ;
        RECT 66.355 205.880 73.355 206.280 ;
        RECT 66.355 205.130 66.755 205.880 ;
        RECT 64.655 204.730 66.755 205.130 ;
        RECT 64.855 202.030 66.355 204.730 ;
        RECT 62.505 200.530 66.355 202.030 ;
        RECT 56.255 199.955 57.955 200.355 ;
        RECT 21.325 137.575 50.935 167.185 ;
        RECT 22.725 135.185 49.395 137.575 ;
        RECT 52.290 137.240 52.770 167.520 ;
        RECT 55.155 167.185 56.655 197.830 ;
        RECT 62.505 170.920 64.005 200.530 ;
        RECT 66.050 194.590 72.930 194.990 ;
        RECT 66.050 190.930 66.450 194.590 ;
        RECT 65.355 190.830 66.855 190.930 ;
        RECT 64.510 190.430 66.855 190.830 ;
        RECT 65.355 174.680 66.855 190.430 ;
        RECT 72.530 187.405 72.930 194.590 ;
        RECT 72.530 187.005 80.505 187.405 ;
        RECT 65.355 173.180 119.745 174.680 ;
        RECT 62.505 169.420 87.490 170.920 ;
        RECT 53.185 137.575 82.795 167.185 ;
        RECT 6.000 73.465 20.715 135.015 ;
        RECT 21.325 105.575 50.935 135.185 ;
        RECT 22.645 103.185 49.315 105.575 ;
        RECT 52.290 105.240 52.770 135.520 ;
        RECT 54.840 135.185 81.510 137.575 ;
        RECT 84.150 137.240 84.630 167.520 ;
        RECT 85.990 167.185 87.490 169.420 ;
        RECT 85.045 137.575 114.655 167.185 ;
        RECT 53.185 105.575 82.795 135.185 ;
        RECT 21.325 73.575 50.935 103.185 ;
        RECT 22.490 71.185 49.160 73.575 ;
        RECT 52.290 73.240 52.770 103.520 ;
        RECT 54.445 103.185 81.115 105.575 ;
        RECT 84.150 105.240 84.630 135.520 ;
        RECT 86.635 135.185 113.305 137.575 ;
        RECT 116.010 137.240 116.490 167.520 ;
        RECT 118.245 167.185 119.745 173.180 ;
        RECT 116.905 137.575 146.515 167.185 ;
        RECT 85.045 105.575 114.655 135.185 ;
        RECT 53.185 73.575 82.795 103.185 ;
        RECT 21.325 41.575 50.935 71.185 ;
        RECT 52.290 41.240 52.770 71.520 ;
        RECT 54.525 71.185 81.195 73.575 ;
        RECT 84.150 73.240 84.630 103.520 ;
        RECT 86.635 103.185 113.305 105.575 ;
        RECT 116.010 105.240 116.490 135.520 ;
        RECT 118.355 135.185 145.025 137.575 ;
        RECT 147.870 137.240 148.350 167.520 ;
        RECT 116.905 105.575 146.515 135.185 ;
        RECT 85.045 73.575 114.655 103.185 ;
        RECT 53.185 41.575 82.795 71.185 ;
        RECT 84.150 41.240 84.630 71.520 ;
        RECT 86.320 71.185 112.990 73.575 ;
        RECT 116.010 73.240 116.490 103.520 ;
        RECT 119.300 103.185 145.970 105.575 ;
        RECT 147.870 105.240 148.350 135.520 ;
        RECT 116.905 73.575 146.515 103.185 ;
        RECT 85.045 41.575 114.655 71.185 ;
        RECT 116.010 41.240 116.490 71.520 ;
        RECT 118.830 71.185 145.500 73.575 ;
        RECT 147.870 73.240 148.350 103.520 ;
        RECT 116.905 41.575 146.515 71.185 ;
        RECT 147.870 41.240 148.350 71.520 ;
        RECT 95.120 38.215 96.840 38.560 ;
        RECT 94.090 37.870 97.870 38.215 ;
        RECT 93.400 37.525 98.215 37.870 ;
        RECT 93.055 37.185 98.555 37.525 ;
        RECT 93.055 36.840 98.900 37.185 ;
        RECT 92.715 36.495 98.900 36.840 ;
        RECT 92.715 36.150 99.245 36.495 ;
        RECT 92.370 35.810 99.245 36.150 ;
        RECT 92.370 35.120 99.590 35.810 ;
        RECT 92.025 34.090 99.590 35.120 ;
        RECT 91.680 33.745 99.590 34.090 ;
        RECT 91.340 32.370 99.930 33.745 ;
        RECT 90.995 30.995 100.275 32.370 ;
        RECT 107.840 31.340 109.900 31.685 ;
        RECT 107.150 30.995 110.930 31.340 ;
        RECT 90.650 30.650 100.275 30.995 ;
        RECT 106.805 30.650 111.620 30.995 ;
        RECT 90.650 29.965 100.620 30.650 ;
        RECT 106.465 30.310 111.965 30.650 ;
        RECT 106.120 29.965 111.965 30.310 ;
        RECT 90.305 29.620 100.620 29.965 ;
        RECT 90.305 29.275 95.120 29.620 ;
        RECT 89.965 28.935 95.120 29.275 ;
        RECT 41.840 28.590 68.305 28.935 ;
        RECT 40.465 28.245 68.305 28.590 ;
        RECT 39.775 27.900 68.305 28.245 ;
        RECT 39.090 27.560 68.305 27.900 ;
        RECT 38.745 27.215 68.305 27.560 ;
        RECT 38.055 26.870 68.305 27.215 ;
        RECT 37.715 26.185 68.305 26.870 ;
        RECT 37.370 25.840 68.305 26.185 ;
        RECT 37.025 25.150 68.305 25.840 ;
        RECT 36.680 24.465 68.305 25.150 ;
        RECT 36.340 23.775 68.305 24.465 ;
        RECT 36.340 23.435 42.525 23.775 ;
        RECT 59.025 23.435 68.305 23.775 ;
        RECT 36.340 22.745 41.840 23.435 ;
        RECT 36.340 22.060 41.495 22.745 ;
        RECT 59.370 22.400 68.305 23.435 ;
        RECT 72.430 28.590 95.120 28.935 ;
        RECT 96.150 28.935 100.620 29.620 ;
        RECT 105.775 29.620 112.305 29.965 ;
        RECT 105.775 29.275 112.650 29.620 ;
        RECT 105.430 28.935 112.650 29.275 ;
        RECT 72.430 27.560 94.775 28.590 ;
        RECT 96.150 27.900 100.965 28.935 ;
        RECT 105.090 28.590 112.650 28.935 ;
        RECT 105.090 27.900 112.995 28.590 ;
        RECT 96.495 27.560 100.965 27.900 ;
        RECT 72.430 26.185 94.430 27.560 ;
        RECT 96.495 26.525 101.305 27.560 ;
        RECT 104.745 27.215 112.995 27.900 ;
        RECT 104.400 26.870 112.995 27.215 ;
        RECT 72.430 25.150 94.090 26.185 ;
        RECT 96.840 25.840 101.305 26.525 ;
        RECT 104.055 26.185 112.995 26.870 ;
        RECT 72.430 23.435 93.745 25.150 ;
        RECT 96.840 24.810 101.650 25.840 ;
        RECT 103.715 25.495 112.995 26.185 ;
        RECT 103.370 24.810 112.995 25.495 ;
        RECT 97.180 24.465 101.650 24.810 ;
        RECT 97.180 23.775 101.995 24.465 ;
        RECT 103.025 24.120 112.995 24.810 ;
        RECT 102.680 23.775 112.995 24.120 ;
        RECT 72.430 22.745 93.400 23.435 ;
        RECT 97.525 22.745 112.995 23.775 ;
        RECT 72.430 22.400 93.055 22.745 ;
        RECT 97.525 22.060 107.150 22.745 ;
        RECT 36.340 21.715 41.840 22.060 ;
        RECT 36.340 21.370 42.180 21.715 ;
        RECT 97.525 21.370 106.805 22.060 ;
        RECT 36.340 21.025 42.525 21.370 ;
        RECT 36.340 20.685 43.555 21.025 ;
        RECT 97.870 20.685 106.465 21.370 ;
        RECT 36.680 20.340 44.930 20.685 ;
        RECT 36.680 19.995 45.620 20.340 ;
        RECT 98.215 19.995 106.120 20.685 ;
        RECT 36.680 19.650 46.650 19.995 ;
        RECT 59.025 19.650 93.055 19.995 ;
        RECT 37.025 19.310 46.995 19.650 ;
        RECT 37.025 18.965 47.680 19.310 ;
        RECT 58.680 18.965 93.400 19.650 ;
        RECT 98.215 19.310 105.775 19.995 ;
        RECT 98.555 18.965 105.775 19.310 ;
        RECT 37.370 18.620 48.025 18.965 ;
        RECT 58.340 18.620 93.745 18.965 ;
        RECT 37.715 18.275 48.715 18.620 ;
        RECT 38.055 17.935 49.055 18.275 ;
        RECT 57.995 17.935 94.090 18.620 ;
        RECT 98.555 18.275 105.430 18.965 ;
        RECT 38.400 17.590 49.055 17.935 ;
        RECT 39.090 17.245 49.400 17.590 ;
        RECT 57.650 17.245 94.430 17.935 ;
        RECT 98.900 17.590 105.090 18.275 ;
        RECT 39.430 16.900 49.745 17.245 ;
        RECT 40.120 16.560 49.745 16.900 ;
        RECT 57.305 16.900 94.775 17.245 ;
        RECT 98.900 16.900 104.745 17.590 ;
        RECT 57.305 16.560 95.120 16.900 ;
        RECT 99.245 16.560 104.400 16.900 ;
        RECT 40.805 16.215 50.090 16.560 ;
        RECT 56.965 16.215 95.120 16.560 ;
        RECT 99.590 16.215 104.055 16.560 ;
        RECT 41.840 15.870 50.090 16.215 ;
        RECT 42.525 15.525 50.430 15.870 ;
        RECT 56.620 15.525 95.465 16.215 ;
        RECT 99.930 15.870 103.715 16.215 ;
        RECT 100.965 15.525 103.025 15.870 ;
        RECT 43.900 15.185 50.430 15.525 ;
        RECT 56.275 15.185 95.805 15.525 ;
        RECT 44.245 14.840 50.430 15.185 ;
        RECT 44.590 14.495 50.430 14.840 ;
        RECT 55.930 14.495 96.150 15.185 ;
        RECT 44.930 12.090 50.430 14.495 ;
        RECT 55.590 14.150 96.495 14.495 ;
        RECT 55.590 13.810 96.840 14.150 ;
        RECT 55.245 13.465 96.840 13.810 ;
        RECT 107.840 13.465 112.995 22.745 ;
        RECT 54.900 13.120 97.180 13.465 ;
        RECT 54.900 12.775 97.525 13.120 ;
        RECT 54.555 12.435 97.870 12.775 ;
        RECT 44.590 11.745 50.430 12.090 ;
        RECT 54.215 12.090 97.870 12.435 ;
        RECT 107.840 12.090 113.340 13.465 ;
        RECT 54.215 11.745 98.215 12.090 ;
        RECT 43.900 11.400 50.430 11.745 ;
        RECT 53.870 11.400 98.215 11.745 ;
        RECT 107.840 11.745 113.680 12.090 ;
        RECT 107.840 11.400 114.025 11.745 ;
        RECT 43.555 11.060 50.090 11.400 ;
        RECT 53.870 11.060 98.555 11.400 ;
        RECT 21.215 10.715 50.090 11.060 ;
        RECT 20.870 10.370 50.090 10.715 ;
        RECT 53.525 10.715 98.555 11.060 ;
        RECT 107.840 11.060 114.370 11.400 ;
        RECT 53.525 10.370 98.900 10.715 ;
        RECT 107.840 10.370 127.090 11.060 ;
        RECT 20.870 10.025 49.745 10.370 ;
        RECT 53.180 10.025 99.245 10.370 ;
        RECT 20.870 9.340 49.400 10.025 ;
        RECT 52.840 9.685 99.245 10.025 ;
        RECT 52.840 9.340 99.590 9.685 ;
        RECT 108.180 9.340 127.090 10.370 ;
        RECT 20.870 8.995 49.055 9.340 ;
        RECT 52.495 8.995 99.930 9.340 ;
        RECT 20.870 8.650 48.715 8.995 ;
        RECT 52.150 8.650 99.930 8.995 ;
        RECT 20.870 8.310 48.370 8.650 ;
        RECT 52.150 8.310 100.275 8.650 ;
        RECT 108.525 8.310 127.090 9.340 ;
        RECT 20.870 7.620 48.025 8.310 ;
        RECT 51.805 7.965 100.275 8.310 ;
        RECT 51.805 7.620 100.620 7.965 ;
        RECT 108.870 7.620 127.090 8.310 ;
        RECT 20.870 6.590 127.090 7.620 ;
        RECT 16.570 0.000 17.470 1.000 ;
        RECT 35.890 0.000 36.790 1.000 ;
        RECT 55.210 0.000 56.110 1.000 ;
        RECT 74.530 0.000 75.430 1.000 ;
        RECT 93.850 0.000 94.750 1.000 ;
        RECT 113.170 0.000 114.070 1.000 ;
        RECT 132.490 0.000 133.390 1.000 ;
        RECT 151.810 0.000 152.710 1.000 ;
  END
END tt_um_tetrahedral_oscillator
END LIBRARY

